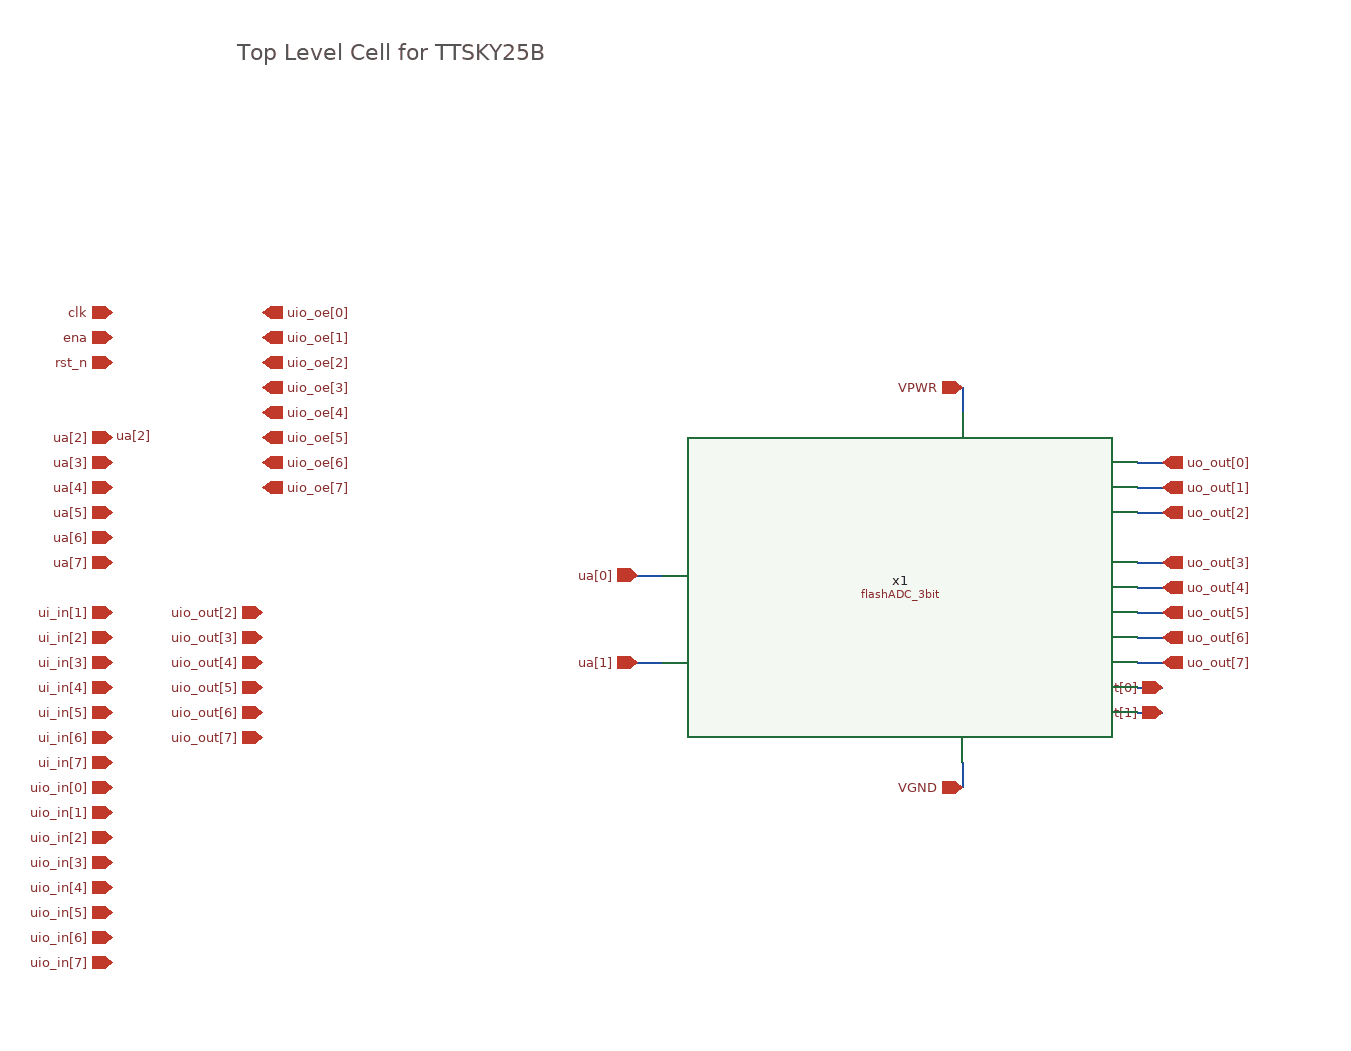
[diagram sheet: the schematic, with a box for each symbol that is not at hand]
v {xschem version=3.4.8RC file_version=1.3}
G {}
K {}
V {}
S {}
F {}
E {}
T {Top Level Cell for TTSKY25B} -240 -520 0 0 1 1 {}
N 80 -90 100 -90 {lab=ua[0]}
N 80 -20 100 -20 {lab=ua[1]}
N 340 60 340 80 {lab=VGND}
N 340 -240 340 -220 {lab=VPWR}
N 480 -180 500 -180 {lab=uo_out[0]}
N 480 -160 500 -160 {lab=uo_out[1]}
N 480 -140 500 -140 {lab=uo_out[2]}
N 480 -100 500 -100 {lab=uo_out[3]}
N 480 -80 500 -80 {lab=uo_out[4]}
N 480 -60 500 -60 {lab=uo_out[5]}
N 480 -40 500 -40 {lab=uo_out[6]}
N 480 -20 500 -20 {lab=uo_out[7]}
N 480 0 500 0 {lab=uio_out[0]}
N 480 20 490 20 {lab=uio_out[1]}
N 490 20 500 20 {lab=uio_out[1]}
C {devices/ipin.sym} -340 -300 0 0 {name=p0 lab=clk}
C {devices/ipin.sym} -340 -280 0 0 {name=p1 lab=ena}
C {devices/ipin.sym} -340 -260 0 0 {name=p2 lab=rst_n}
C {devices/ipin.sym} -340 -180 0 0 {name=p6 lab=ua[3]}
C {devices/ipin.sym} -340 -160 0 0 {name=p7 lab=ua[4]}
C {devices/ipin.sym} -340 -140 0 0 {name=p14 lab=ua[5]}
C {devices/ipin.sym} -340 -120 0 0 {name=p9 lab=ua[6]}
C {devices/ipin.sym} -340 -100 0 0 {name=p10 lab=ua[7]}
C {devices/ipin.sym} -340 -60 0 0 {name=p12 lab=ui_in[1]}
C {devices/ipin.sym} -340 -40 0 0 {name=p13 lab=ui_in[2]}
C {devices/ipin.sym} -340 -20 0 0 {name=p8 lab=ui_in[3]}
C {devices/ipin.sym} -340 0 0 0 {name=p15 lab=ui_in[4]}
C {devices/ipin.sym} -340 20 0 0 {name=p16 lab=ui_in[5]}
C {devices/ipin.sym} -340 40 0 0 {name=p17 lab=ui_in[6]}
C {devices/ipin.sym} -340 60 0 0 {name=p18 lab=ui_in[7]}
C {devices/ipin.sym} -340 80 0 0 {name=p19 lab=uio_in[0]}
C {devices/ipin.sym} -340 100 0 0 {name=p20 lab=uio_in[1]}
C {devices/ipin.sym} -340 120 0 0 {name=p21 lab=uio_in[2]}
C {devices/ipin.sym} -340 140 0 0 {name=p22 lab=uio_in[3]}
C {devices/ipin.sym} -340 160 0 0 {name=p23 lab=uio_in[4]}
C {devices/ipin.sym} -340 180 0 0 {name=p24 lab=uio_in[5]}
C {devices/ipin.sym} -340 200 0 0 {name=p25 lab=uio_in[6]}
C {devices/ipin.sym} -340 220 0 0 {name=p26 lab=uio_in[7]}
C {devices/opin.sym} -220 -300 0 0 {name=p27 lab=uio_oe[0]}
C {devices/opin.sym} -220 -280 0 0 {name=p28 lab=uio_oe[1]}
C {devices/opin.sym} -220 -260 0 0 {name=p29 lab=uio_oe[2]}
C {devices/opin.sym} -220 -240 0 0 {name=p30 lab=uio_oe[3]}
C {devices/opin.sym} -220 -220 0 0 {name=p31 lab=uio_oe[4]}
C {devices/opin.sym} -220 -200 0 0 {name=p32 lab=uio_oe[5]}
C {devices/opin.sym} -220 -180 0 0 {name=p33 lab=uio_oe[6]}
C {devices/opin.sym} -220 -160 0 0 {name=p34 lab=uio_oe[7]}
C {devices/opin.sym} 500 -160 0 0 {name=p36 lab=uo_out[1]}
C {devices/opin.sym} 500 -140 0 0 {name=p37 lab=uo_out[2]}
C {devices/opin.sym} 500 -100 0 0 {name=p38 lab=uo_out[3]}
C {devices/opin.sym} 500 -80 0 0 {name=p39 lab=uo_out[4]}
C {devices/opin.sym} 500 -60 0 0 {name=p40 lab=uo_out[5]}
C {devices/opin.sym} 500 -40 0 0 {name=p41 lab=uo_out[6]}
C {devices/opin.sym} 500 -20 0 0 {name=p42 lab=uo_out[7]}
C {devices/noconn.sym} -340 -300 0 1 {name=l1}
C {devices/noconn.sym} -340 -280 0 1 {name=l2}
C {devices/noconn.sym} -340 -260 0 1 {name=l3}
C {devices/noconn.sym} -340 -180 0 1 {name=l7}
C {devices/noconn.sym} -340 -120 0 1 {name=l8}
C {devices/noconn.sym} -340 -80 0 1 {name=l25}
C {devices/noconn.sym} -340 -60 0 1 {name=l26}
C {devices/noconn.sym} -340 -40 0 1 {name=l27}
C {devices/noconn.sym} -340 -20 0 1 {name=l28}
C {devices/noconn.sym} -340 0 0 1 {name=l29}
C {devices/noconn.sym} -340 20 0 1 {name=l30}
C {devices/noconn.sym} -340 40 0 1 {name=l31}
C {devices/noconn.sym} -340 60 0 1 {name=l32}
C {devices/noconn.sym} -340 80 0 1 {name=l33}
C {devices/noconn.sym} -340 100 0 1 {name=l34}
C {devices/noconn.sym} -340 120 0 1 {name=l35}
C {devices/noconn.sym} -340 140 0 1 {name=l36}
C {devices/noconn.sym} -340 160 0 1 {name=l37}
C {devices/noconn.sym} -340 180 0 1 {name=l38}
C {devices/noconn.sym} -340 200 0 1 {name=l39}
C {devices/noconn.sym} -340 220 0 1 {name=l40}
C {devices/noconn.sym} -220 -300 0 0 {name=l41}
C {devices/noconn.sym} -220 -280 0 0 {name=l42}
C {devices/noconn.sym} -220 -260 0 0 {name=l43}
C {devices/noconn.sym} -220 -240 0 0 {name=l44}
C {devices/noconn.sym} -220 -220 0 0 {name=l45}
C {devices/noconn.sym} -220 -200 0 0 {name=l46}
C {devices/noconn.sym} -220 -180 0 0 {name=l47}
C {devices/noconn.sym} -220 -160 0 0 {name=l48}
C {devices/iopin.sym} 500 0 0 0 {name=p45 lab=uio_out[0]}
C {devices/iopin.sym} 500 20 0 0 {name=p46 lab=uio_out[1]}
C {devices/iopin.sym} -220 -60 0 0 {name=p47 lab=uio_out[2]}
C {devices/noconn.sym} -220 -60 0 0 {name=l11}
C {devices/iopin.sym} -220 -40 0 0 {name=p48 lab=uio_out[3]}
C {devices/noconn.sym} -220 -40 0 0 {name=l12}
C {devices/iopin.sym} -220 -20 0 0 {name=p49 lab=uio_out[4]}
C {devices/noconn.sym} -220 -20 0 0 {name=l13}
C {devices/iopin.sym} -220 0 0 0 {name=p50 lab=uio_out[5]}
C {devices/noconn.sym} -220 0 0 0 {name=l14}
C {devices/iopin.sym} -220 20 0 0 {name=p51 lab=uio_out[6]}
C {devices/noconn.sym} -220 20 0 0 {name=l15}
C {devices/iopin.sym} -220 40 0 0 {name=p52 lab=uio_out[7]}
C {devices/noconn.sym} -220 40 0 0 {name=l16}
C {devices/noconn.sym} -340 -140 0 1 {name=l17}
C {devices/noconn.sym} -340 -160 0 1 {name=l18}
C {devices/noconn.sym} -340 -100 0 1 {name=l4}
C {/home/bmott/ttsky25b_tiny_chaos/xsch/ip/adc/flashADC_3bit.sym} 290 -90 0 0 {name=x1}
C {devices/ipin.sym} 80 -90 0 0 {name=p3 lab=ua[0]}
C {devices/ipin.sym} -340 -200 0 0 {name=p4 lab=ua[2]}
C {devices/noconn.sym} -340 -200 0 1 {name=l5
lab=ua[2]}
C {devices/ipin.sym} 80 -20 0 0 {name=p5 lab=ua[1]}
C {devices/iopin.sym} 340 -240 3 0 {name=p11 lab=VPWR}
C {devices/iopin.sym} 340 80 1 0 {name=p35 lab=VGND}
C {devices/opin.sym} 500 -180 0 0 {name=p43 lab=uo_out[0]}
